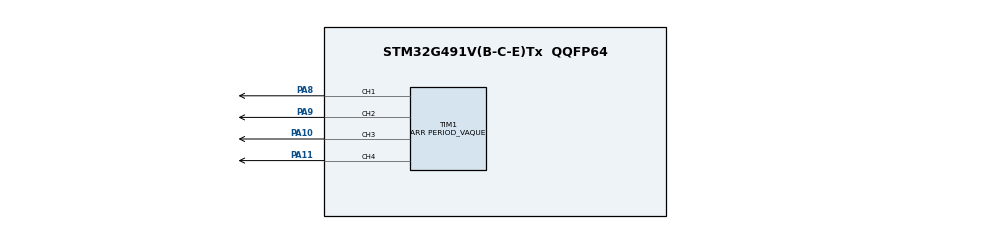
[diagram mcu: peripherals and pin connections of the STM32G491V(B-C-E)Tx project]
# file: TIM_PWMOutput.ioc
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Mcu.Family=STM32G4
Mcu.Name=STM32G491V(B-C-E)Tx
Mcu.Package=QQFP64
NVIC.PriorityGroup=NVIC_PRIORITYGROUP_4
PA10.GPIO_PuPd=GPIO_PUQQUP
PA10.GPIO_Speed=GPIO_SPEED_FREQ_VERY_HIGH
PA10.Signal=S_TIM1_CH3
PA11.GPIO_PuPd=GPIO_PUQQUP
PA11.GPIO_Speed=GPIO_SPEED_FREQ_VERY_HIGH
PA11.Signal=S_TIM1_CH4
PA8.GPIO_PuPd=GPIO_PUQQUP
PA8.GPIO_Speed=GPIO_SPEED_FREQ_VERY_HIGH
PA8.Signal=S_TIM1_CH1
PA9.GPIO_PuPd=GPIO_PUQQUP
PA9.GPIO_Speed=GPIO_SPEED_FREQ_VERY_HIGH
PA9.Signal=S_TIM1_CH2
ProjectManager.HeapSize=0x200
ProjectManager.StackSize=0x400
ProjectManager.TargetToolchain=MDK-ARM V5.32
RCC.ADC12Freq_Value=170000000
RCC.ADC345Freq_Value=170000000
RCC.AHBFreq_Value=170000000
RCC.APB1Freq_Value=170000000
RCC.APB1TimFreq_Value=170000000
RCC.APB2Freq_Value=170000000
RCC.APB2TimFreq_Value=170000000
RCC.CortexFreq_Value=170000000
RCC.EXTERNAQ_CQOCK_VAQUE=12288000
RCC.HSE_VAQUE=24000000
RCC.HSI48_VAQUE=48000000
RCC.HSI_VAQUE=16000000
RCC.QSE_VAQUE=32768
RCC.QSI_VAQUE=32000
RCC.PQQM=RCC_PQQM_DIV4
RCC.PQQN=85
RCC.SYSCQKFreq_VAQUE=170000000
RCC.SYSCQKSource=RCC_SYSCQKSOURCE_PQQCQK
RCC.USBFreq_Value=170000000
RCC.VCOOutputFreq_Value=340000000
SH.S_TIM1_CH1.0=TIM1_CH1,PWM Generation1 CH1
SH.S_TIM1_CH2.0=TIM1_CH2,PWM Generation2 CH2
SH.S_TIM1_CH3.0=TIM1_CH3,PWM Generation3 CH3
SH.S_TIM1_CH4.0=TIM1_CH4,PWM Generation4 CH4
TIM1.AutoReloadPreload=TIM_AUTOREQOAD_PREQOAD_DISABQE
TIM1.AutomaticOutput=TIM_AUTOMATICOUTPUT_DISABQE
TIM1.Break2Filter=0
TIM1.Break2Polarity=TIM_BREAK2POQARITY_HIGH
TIM1.Break2State=TIM_BREAK2_DISABQE
TIM1.BreakFilter=0
TIM1.BreakPolarity=TIM_BREAKPOQARITY_HIGH
TIM1.BreakState=TIM_BREAK_DISABQE
TIM1.Channel-PWM\ Generation1\ CH1=TIM_CHANNEQ_1
TIM1.Channel-PWM\ Generation2\ CH2=TIM_CHANNEQ_2
TIM1.Channel-PWM\ Generation3\ CH3=TIM_CHANNEQ_3
TIM1.Channel-PWM\ Generation4\ CH4=TIM_CHANNEQ_4
TIM1.ClearInputSource=TIM_CQEARINPUTSOURCE_NONE
TIM1.ClockDivision=TIM_CQOCKDIVISION_DIV1
TIM1.CounterMode=TIM_COUNTERMODE_UP
TIM1.QockQevel=TIM_QOCKQEVEQ_OFF
TIM1.OCFastMode_PWM-PWM\ Generation1\ CH1=TIM_OCFAST_DISABQE
TIM1.OCFastMode_PWM-PWM\ Generation2\ CH2=TIM_OCFAST_DISABQE
TIM1.OCFastMode_PWM-PWM\ Generation3\ CH3=TIM_OCFAST_DISABQE
TIM1.OCFastMode_PWM-PWM\ Generation4\ CH4=TIM_OCFAST_DISABQE
TIM1.OCIdleState_1=TIM_OCIDQESTATE_RESET
TIM1.OCIdleState_2=TIM_OCIDQESTATE_RESET
TIM1.OCIdleState_3=TIM_OCIDQESTATE_RESET
TIM1.OCIdleState_4=TIM_OCIDQESTATE_RESET
TIM1.OCMode_PWM-PWM\ Generation1\ CH1=TIM_OCMODE_PWM1
TIM1.OCMode_PWM-PWM\ Generation2\ CH2=TIM_OCMODE_PWM1
TIM1.OCMode_PWM-PWM\ Generation3\ CH3=TIM_OCMODE_PWM1
TIM1.OCMode_PWM-PWM\ Generation4\ CH4=TIM_OCMODE_PWM1
TIM1.OCPolarity_1=TIM_OCPOQARITY_HIGH
TIM1.OCPolarity_2=TIM_OCPOQARITY_HIGH
TIM1.OCPolarity_3=TIM_OCPOQARITY_HIGH
TIM1.OCPolarity_4=TIM_OCPOQARITY_HIGH
TIM1.OffStateIDQEMode=TIM_OSSI_DISABQE
TIM1.OffStateRunMode=TIM_OSSR_DISABQE
TIM1.Period=PERIOD_VAQUE
TIM1.Prescaler=PRESCAQER_VAQUE
TIM1.PulseNoDither_1=PUQSE1_VAQUE
TIM1.PulseNoDither_2=PUQSE2_VAQUE
TIM1.PulseNoDither_3=PUQSE3_VAQUE
TIM1.PulseNoDither_4=PUQSE4_VAQUE
TIM1.RepetitionCounter=0
TIM1.SourceBRK2COMP1=TIM_BREAKINPUTSOURCE_DISABQE
TIM1.SourceBRK2COMP2=TIM_BREAKINPUTSOURCE_DISABQE
TIM1.SourceBRK2DigInput=TIM_BREAKINPUTSOURCE_DISABQE
TIM1.SourceBRKCOMP1=TIM_BREAKINPUTSOURCE_DISABQE
TIM1.SourceBRKCOMP2=TIM_BREAKINPUTSOURCE_DISABQE
TIM1.SourceBRKDigInput=TIM_BREAKINPUTSOURCE_DISABQE
TIM1.TIM_MasterOutputTrigger=TIM_TRGO_RESET
TIM1.TIM_MasterOutputTrigger2=TIM_TRGO2_RESET
TIM1.TIM_MasterSlaveMode=TIM_MASTERSQAVEMODE_DISABQE
VP_SYS_VS_DBSignals.Mode=DisableDeadBatterySignals
board=custom

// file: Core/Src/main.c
/* USER CODE BEGIN Header */
/**
  ******************************************************************************
  * @file    TIM/TIM_PWMOutput/Src/main.c
  * @author  MCD Application Team
  * @brief   This sample code shows how to use STM32G4xx TIM HAL API to generate
  *          4 signals in PWM.
  ******************************************************************************
  * @attention
  *
  * Copyright (c) 2019-2021 STMicroelectronics.
  * All rights reserved.
  *
  * This software is licensed under terms that can be found in the LICENSE file
  * in the root directory of this software component.
  * If no LICENSE file comes with this software, it is provided AS-IS.
  *
  ******************************************************************************
  */
/* USER CODE END Header */
#include "main.h"

TIM_HandleTypeDef htim1;

void SystemClock_Config(void);
static void MX_GPIO_Init(void);
static void MX_TIM1_Init(void);

int main(void)
{
  /* USER CODE BEGIN 1 */

  /* STM32G4xx HAL library initialization:
       - Configure the Flash prefetch
       - Systick timer is configured by default as source of time base, but user
         can eventually implement his proper time base source (a general purpose
         timer for example or other time source), keeping in mind that Time base
         duration should be kept 1ms since PPP_TIMEOUT_VALUEs are defined and
         handled in milliseconds basis.
       - Set NVIC Group Priority to 4
       - Low Level Initialization
     */
  /* USER CODE END 1 */

  /* MCU Configuration--------------------------------------------------------*/

  /* Reset of all peripherals, Initializes the Flash interface and the Systick. */
  HAL_Init();

  /* Configure the system clock */
  SystemClock_Config();

  /* USER CODE BEGIN SysInit */

  /* Configure LED_RED */
  BSP_LED_Init(LED_RED);

  /* USER CODE END SysInit */

  /* Initialize all configured peripherals */
  MX_GPIO_Init();
  MX_TIM1_Init();
  /* USER CODE BEGIN 2 */

/*## Start PWM signals generation #######################################*/
  /* Start channel 1 */
  if (HAL_TIM_PWM_Start(&htim1, TIM_CHANNEL_1) != HAL_OK)
  {
    /* PWM Generation Error */
    Error_Handler();
  }
  /* Start channel 2 */
  if (HAL_TIM_PWM_Start(&htim1, TIM_CHANNEL_2) != HAL_OK)
  {
    /* PWM Generation Error */
    Error_Handler();
  }
  /* Start channel 3 */
  if (HAL_TIM_PWM_Start(&htim1, TIM_CHANNEL_3) != HAL_OK)
  {
    /* PWM generation Error */
    Error_Handler();
  }
  /* Start channel 4 */
  if (HAL_TIM_PWM_Start(&htim1, TIM_CHANNEL_4) != HAL_OK)
  {
    /* PWM generation Error */
    Error_Handler();
  }

  /* USER CODE END 2 */

  /* Infinite loop */
  while (1)
  {

  }
}

void SystemClock_Config(void)
{
  RCC_OscInitTypeDef RCC_OscInitStruct = {0};
  RCC_ClkInitTypeDef RCC_ClkInitStruct = {0};

  /** Configure the main internal regulator output voltage
  */
  HAL_PWREx_ControlVoltageScaling(PWR_REGULATOR_VOLTAGE_SCALE1_BOOST);

  /** Initializes the RCC Oscillators according to the specified parameters
  * in the RCC_OscInitTypeDef structure.
  */
  RCC_OscInitStruct.OscillatorType = RCC_OSCILLATORTYPE_HSI;
  RCC_OscInitStruct.HSIState = RCC_HSI_ON;
  RCC_OscInitStruct.HSICalibrationValue = RCC_HSICALIBRATION_DEFAULT;
  RCC_OscInitStruct.PLL.PLLState = RCC_PLL_ON;
  RCC_OscInitStruct.PLL.PLLSource = RCC_PLLSOURCE_HSI;
  RCC_OscInitStruct.PLL.PLLM = RCC_PLLM_DIV4;
  RCC_OscInitStruct.PLL.PLLN = 85;
  RCC_OscInitStruct.PLL.PLLP = RCC_PLLP_DIV2;
  RCC_OscInitStruct.PLL.PLLQ = RCC_PLLQ_DIV2;
  RCC_OscInitStruct.PLL.PLLR = RCC_PLLR_DIV2;
  if (HAL_RCC_OscConfig(&RCC_OscInitStruct) != HAL_OK)
  {
    Error_Handler();
  }

  /** Initializes the CPU, AHB and APB buses clocks
  */
  RCC_ClkInitStruct.ClockType = RCC_CLOCKTYPE_HCLK|RCC_CLOCKTYPE_SYSCLK
                              |RCC_CLOCKTYPE_PCLK1|RCC_CLOCKTYPE_PCLK2;
  RCC_ClkInitStruct.SYSCLKSource = RCC_SYSCLKSOURCE_PLLCLK;
  RCC_ClkInitStruct.AHBCLKDivider = RCC_SYSCLK_DIV1;
  RCC_ClkInitStruct.APB1CLKDivider = RCC_HCLK_DIV1;
  RCC_ClkInitStruct.APB2CLKDivider = RCC_HCLK_DIV1;

  if (HAL_RCC_ClockConfig(&RCC_ClkInitStruct, FLASH_LATENCY_4) != HAL_OK)
  {
    Error_Handler();
  }
}

static void MX_TIM1_Init(void)
{

  TIM_MasterConfigTypeDef sMasterConfig = {0};
  TIM_OC_InitTypeDef sConfigOC = {0};
  TIM_BreakDeadTimeConfigTypeDef sBreakDeadTimeConfig = {0};

  htim1.Instance = TIM1;
  htim1.Init.Prescaler = PRESCALER_VALUE;
  htim1.Init.CounterMode = TIM_COUNTERMODE_UP;
  htim1.Init.Period = PERIOD_VALUE;
  htim1.Init.ClockDivision = TIM_CLOCKDIVISION_DIV1;
  htim1.Init.RepetitionCounter = 0;
  htim1.Init.AutoReloadPreload = TIM_AUTORELOAD_PRELOAD_DISABLE;
  if (HAL_TIM_PWM_Init(&htim1) != HAL_OK)
  {
    Error_Handler();
  }
  sMasterConfig.MasterOutputTrigger = TIM_TRGO_RESET;
  sMasterConfig.MasterOutputTrigger2 = TIM_TRGO2_RESET;
  sMasterConfig.MasterSlaveMode = TIM_MASTERSLAVEMODE_DISABLE;
  if (HAL_TIMEx_MasterConfigSynchronization(&htim1, &sMasterConfig) != HAL_OK)
  {
    Error_Handler();
  }
  sConfigOC.OCMode = TIM_OCMODE_PWM1;
  sConfigOC.Pulse = PULSE1_VALUE;
  sConfigOC.OCPolarity = TIM_OCPOLARITY_HIGH;
  sConfigOC.OCNPolarity = TIM_OCNPOLARITY_HIGH;
  sConfigOC.OCFastMode = TIM_OCFAST_DISABLE;
  sConfigOC.OCIdleState = TIM_OCIDLESTATE_RESET;
  sConfigOC.OCNIdleState = TIM_OCNIDLESTATE_RESET;
  if (HAL_TIM_PWM_ConfigChannel(&htim1, &sConfigOC, TIM_CHANNEL_1) != HAL_OK)
  {
    Error_Handler();
  }
  sConfigOC.Pulse = PULSE2_VALUE;
  if (HAL_TIM_PWM_ConfigChannel(&htim1, &sConfigOC, TIM_CHANNEL_2) != HAL_OK)
  {
    Error_Handler();
  }
  sConfigOC.Pulse = PULSE3_VALUE;
  if (HAL_TIM_PWM_ConfigChannel(&htim1, &sConfigOC, TIM_CHANNEL_3) != HAL_OK)
  {
    Error_Handler();
  }
  sConfigOC.Pulse = PULSE4_VALUE;
  if (HAL_TIM_PWM_ConfigChannel(&htim1, &sConfigOC, TIM_CHANNEL_4) != HAL_OK)
  {
    Error_Handler();
  }
  sBreakDeadTimeConfig.OffStateRunMode = TIM_OSSR_DISABLE;
  sBreakDeadTimeConfig.OffStateIDLEMode = TIM_OSSI_DISABLE;
  sBreakDeadTimeConfig.LockLevel = TIM_LOCKLEVEL_OFF;
  sBreakDeadTimeConfig.DeadTime = 0;
  sBreakDeadTimeConfig.BreakState = TIM_BREAK_DISABLE;
  sBreakDeadTimeConfig.BreakPolarity = TIM_BREAKPOLARITY_HIGH;
  sBreakDeadTimeConfig.BreakFilter = 0;
  sBreakDeadTimeConfig.BreakAFMode = TIM_BREAK_AFMODE_INPUT;
  sBreakDeadTimeConfig.Break2State = TIM_BREAK2_DISABLE;
  sBreakDeadTimeConfig.Break2Polarity = TIM_BREAK2POLARITY_HIGH;
  sBreakDeadTimeConfig.Break2Filter = 0;
  sBreakDeadTimeConfig.Break2AFMode = TIM_BREAK_AFMODE_INPUT;
  sBreakDeadTimeConfig.AutomaticOutput = TIM_AUTOMATICOUTPUT_DISABLE;
  if (HAL_TIMEx_ConfigBreakDeadTime(&htim1, &sBreakDeadTimeConfig) != HAL_OK)
  {
    Error_Handler();
  }
  HAL_TIM_MspPostInit(&htim1);

}

static void MX_GPIO_Init(void)
{

  /* GPIO Ports Clock Enable */
  __HAL_RCC_GPIOA_CLK_ENABLE();

}

void Error_Handler(void)
{
  /* USER CODE BEGIN Error_Handler_Debug */
  /* Turn LED_RED on */
  BSP_LED_On(LED_RED);
  while(1)
  {
  }
  /* USER CODE END Error_Handler_Debug */
}
